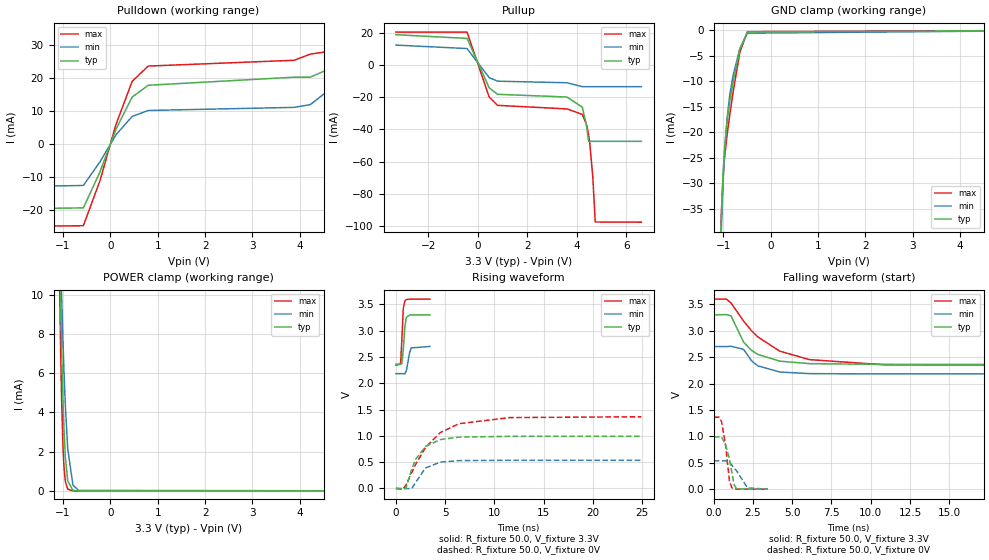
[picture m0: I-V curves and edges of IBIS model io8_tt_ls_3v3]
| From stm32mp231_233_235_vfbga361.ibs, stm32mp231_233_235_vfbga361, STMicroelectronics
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[Model]   io8_tt_ls_3v3
Model_type I/O
Polarity   Non-Inverting
Enable   Active-Low
| CAP_THRESHOLD on pad IOTT is "UDTCAPC" :
| Rising=30.0% of vddiov33m   Falling=70.0% of vddiov33m
| C_comp min and max val. don't necessarily correlate with the min and max pvt
| but are the smallest and greatest pad capacitance found.
| var   typ   min   max
C_comp   1.23988pF  995.26945fF  2.17617pF
|C_comp_pullup   730.17000fF  473.44500fF  1.67079pF
|C_comp_pulldown   509.70500fF  521.82445fF  505.38500fF
Vinl = 810.0mV
Vinh = 2.52V
Vmeas = 1.65V   | Reference voltage for timing measurements
Cref  = 50.0pF   | Timing specification test load capacitance value
Rref  = 100.0MOhm   | Timing specification test load resistance value
Vref  = 1.65V   | Timing specification test load voltage
[Model Spec]
| TIME_THRESHOLD on pin ZIV08M is "CMOS" :
| Rising=50.0% of vddv08m   Falling=50.0% of vddv08m
Vinl 1.08570V 868.70000mV 1.21270V
Vinh 1.55630V 1.26330V 1.71030V
| variable   typ   min   max
[Temperature Range] 25.0 125.0 -40.0
| variable   typ   min   max
[Voltage Range] 3.3V 2.7V 3.6V
| variable   typ   min   max
[POWER Clamp Reference] 3.3V 2.7V 3.6V
| variable   typ   min   max
[GND Clamp Reference] 0V 0V 0V
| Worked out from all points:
|   slope of the pulldown table from 0 to 0.495 V, typ, clamps not added: 34.1 ohm
|   slope of the pullup table from 0 to 0.495 V, typ, clamps not added: 33.8 ohm
|   GND clamp passes 1 mA (typ) near -0.55 V on its own axis
|   POWER clamp passes 1 mA (typ) near -0.93 V on its own axis
|   rising waveform, R_fixture 50.0, V_fixture 3.3V: 20-80 % time 214ps typ, 294ps min, 183ps max; typ from 2.36 V to 3.3 V
|   falling waveform, R_fixture 50.0, V_fixture 3.3V: 20-80 % time 1.45ns typ, 1.13ns min, 2.84ns max; typ from 3.3 V to 2.36 V
|   rising waveform, R_fixture 50.0, V_fixture 0V: 20-80 % time 1.63ns typ, 1.34ns min, 3.19ns max; typ from 0 V to 0.99 V
|   falling waveform, R_fixture 50.0, V_fixture 0V: 20-80 % time 422ps typ, 711ps min, 329ps max; typ from 0.991 V to 0 V
[POWER Clamp]
-3.3V     1.352A     318.4mA    1.997A
-1.07V    12.07mA    13.62mA    10.38mA
-1.06V    10.79mA    12.67mA    8.742mA
-1.05V    9.57mA     11.75mA    7.25mA
-1.03V    7.34mA     9.996mA    4.745mA
-1V       4.587mA    7.593mA    2.212mA
-980mV    3.182mA    6.169mA    1.235mA
-950mV    1.703mA    4.334mA    479uA
-900mV    514.7uA    2.139mA    90.77uA
-790mV    28.73uA    299.9uA    2.711uA
-670mV    1.278uA    27.54uA    387.5nA
6.6V      0A         0A         0A
[GND Clamp]
-3.3V     -3.764A    -3.734A    -3.781A
-1.05V    -39.76mA   -42.44mA   -39.2mA
-1.04V    -36.65mA   -39.24mA   -36.3mA
-1.03V    -33.91mA   -36.36mA   -33.82mA
-1V       -27.43mA   -29.21mA   -28.35mA
-970mV    -22.87mA   -23.78mA   -24.78mA
-920mV    -17.9mA    -17.36mA   -20.6mA
-860mV    -13.88mA   -12.47mA   -16.46mA
-790mV    -10.04mA   -8.727mA   -11.99mA
-650mV    -3.744mA   -3.565mA   -4.327mA
-490mV    -324.2uA   -555.2uA   -259.7uA
6.6V      204.7nA    4.775uA    218.9nA
| variable   typ   min   max
[Pullup Reference] 3.3V 2.7V 3.6V
| variable   typ   min   max
[Pulldown Reference] 0V 0V 0V
[Pullup]
-3.3V     18.7mA     12.28mA    20.34mA
-430mV    16.42mA    10.12mA    20.31mA
460mV     -14.22mA   -7.865mA   -19.9mA
800mV     -18.26mA   -10.12mA   -25.1mA
3.6V      -19.94mA   -11.09mA   -27.33mA
4.22V     -26.27mA   -13.53mA   -30.72mA
4.39V     -38.01mA   -13.53mA   -37.12mA
4.47V     -47.45mA   -13.53mA   -43.21mA
4.52V     -47.45mA   -13.53mA   -48.77mA
4.64V     -47.45mA   -13.53mA   -69.14mA
4.74V     -47.45mA   -13.53mA   -97.47mA
6.6V      -47.45mA   -13.53mA   -97.59mA
[Pulldown]
-3.3V     -19.95mA   -13.29mA   -25.2mA
-570mV    -19.4mA    -12.62mA   -24.8mA
-220mV    -8.542mA   -5.471mA   -11.2mA
120mV     4.438mA    2.727mA    5.906mA
460mV     14.14mA    8.27mA     18.88mA
800mV     17.71mA    10.08mA    23.52mA
3.88V     20.15mA    11.02mA    25.27mA
4.22V     20.15mA    11.84mA    27.13mA
4.56V     22.27mA    15.63mA    27.84mA
4.9V      31.19mA    28.07mA    34.84mA
5.24V     59.66mA    64.92mA    58.18mA
6.6V      396.6mA    415.2mA    364.6mA
[Ramp]
dV/dt_r 594.29848mV/1.6319ns 321.45402mV/1.34002ns 817.90974mV/3.19451ns
dV/dt_f 562.26796mV/1.45398ns 311.02723mV/1.13039ns 753.53423mV/2.84354ns
R_load = 50.0
| Removed startup time: 0s 0s 0s  .
| Removed end time: 3.45ns.
[Rising Waveform]
R_fixture   = 50.0
V_fixture   = 3.3V
V_fixture_min = 2.7V
V_fixture_max = 3.6V
0s        2.363V     2.182V     2.344V
450ps     2.363V     2.182V     2.36V
500ps     2.36V      2.182V     2.455V
600ps     2.374V     2.182V     2.824V
750ps     2.64V      2.181V     3.423V
900ps     3.055V     2.177V     3.563V
1.05ns    3.254V     2.231V     3.59V
1.4ns     3.297V     2.589V     3.599V
1.55ns    3.299V     2.671V     3.599V
3.45ns    3.3V       2.7V       3.6V
| Removed startup time: 0s 0s 0s  .
| Removed end time: 24.9ns.
[Falling Waveform]
R_fixture   = 50.0
V_fixture   = 3.3V
V_fixture_min = 2.7V
V_fixture_max = 3.6V
0s        3.3V       2.7V       3.6V
800ps     3.306V     2.701V     3.599V
1.1ns     3.281V     2.706V     3.526V
1.9ns     2.784V     2.648V     3.183V
2.4ns     2.629V     2.433V     3.002V
2.8ns     2.552V     2.336V     2.884V
4.2ns     2.424V     2.219V     2.614V
6.1ns     2.377V     2.188V     2.453V
10.8ns    2.363V     2.182V     2.357V
24.9ns    2.363V     2.182V     2.344V
| Removed startup time: 0s 0s 0s  .
| Removed end time: 24.9ns.
[Rising Waveform]
R_fixture   = 50.0
V_fixture   = 0V
V_fixture_min = 0V
V_fixture_max = 0V
0s        541.8nV    2.991uV    643.1nV
700ps     -6.602mV   -121.1uV   -13.51mV
1ns       -2.253mV   -2.009mV   58.88mV
1.6ns     365.4mV    -3.671mV   299.5mV
2ns       553.1mV    116mV      458.9mV
3ns       797.7mV    388.7mV    778.2mV
4.5ns     929.4mV    500.3mV    1.062V
6.4ns     976.3mV    529.4mV    1.231V
11.5ns    990.2mV    535.7mV    1.347V
24.9ns    990.5mV    535.8mV    1.363V
| Removed startup time: 0s 0s 0s  .
| Removed end time: 3.45ns.
[Falling Waveform]
R_fixture   = 50.0
V_fixture   = 0V
V_fixture_min = 0V
V_fixture_max = 0V
0s        990.5mV    535.8mV    1.363V
350ps     990.5mV    535.8mV    1.362V
500ps     989mV      535.8mV    1.274V
750ps     840.9mV    535.9mV    837.3mV
1ns       573.6mV    511.9mV    157.2mV
1.15ns    320.2mV    455.4mV    25.06mV
1.3ns     78.82mV    396.8mV    5.973mV
1.45ns    10.84mV    347.9mV    2.621mV
2.15ns    582.6uV    24.57mV    751.1uV
3.45ns    161.2uV    154.9uV    256.1uV
